VERSION 5.7 ;
  NOWIREEXTENSIONATPIN ON ;
  DIVIDERCHAR "/" ;
  BUSBITCHARS "[]" ;
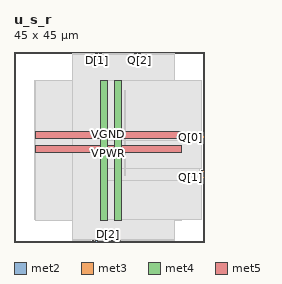
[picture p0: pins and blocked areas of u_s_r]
MACRO u_s_r
  CLASS BLOCK ;
  FOREIGN u_s_r ;
  ORIGIN 0.000 0.000 ;
  SIZE 45.000 BY 45.000 ;
  PIN D[0]
    DIRECTION INPUT ;
    USE SIGNAL ;
    ANTENNAGATEAREA 0.213000 ;
    PORT
      LAYER met2 ;
        RECT 23.090 0.000 23.370 0.280 ;
    END
  END D[0]
  PIN D[1]
    DIRECTION INPUT ;
    USE SIGNAL ;
    ANTENNAGATEAREA 0.213000 ;
    PORT
      LAYER met2 ;
        RECT 19.410 44.720 19.690 45.000 ;
    END
  END D[1]
  PIN D[2]
    DIRECTION INPUT ;
    USE SIGNAL ;
    ANTENNAGATEAREA 0.213000 ;
    PORT
      LAYER met2 ;
        RECT 22.170 0.000 22.450 0.280 ;
    END
  END D[2]
  PIN D[3]
    DIRECTION INPUT ;
    USE SIGNAL ;
    ANTENNAGATEAREA 0.213000 ;
    PORT
      LAYER met2 ;
        RECT 24.930 0.000 25.210 0.280 ;
    END
  END D[3]
  PIN Q[0]
    DIRECTION OUTPUT ;
    USE SIGNAL ;
    ANTENNADIFFAREA 0.702900 ;
    PORT
      LAYER met3 ;
        RECT 44.400 24.520 45.000 25.120 ;
    END
  END Q[0]
  PIN Q[1]
    DIRECTION OUTPUT ;
    USE SIGNAL ;
    ANTENNADIFFAREA 0.702900 ;
    PORT
      LAYER met3 ;
        RECT 44.400 15.000 45.000 15.600 ;
    END
  END Q[1]
  PIN Q[2]
    DIRECTION OUTPUT ;
    USE SIGNAL ;
    ANTENNADIFFAREA 0.702900 ;
    PORT
      LAYER met2 ;
        RECT 29.530 44.720 29.810 45.000 ;
    END
  END Q[2]
  PIN Q[3]
    DIRECTION OUTPUT ;
    USE SIGNAL ;
    ANTENNADIFFAREA 0.702900 ;
    PORT
      LAYER met3 ;
        RECT 44.400 16.360 45.000 16.960 ;
    END
  END Q[3]
  PIN S_in
    DIRECTION INPUT ;
    USE SIGNAL ;
    ANTENNAGATEAREA 0.213000 ;
    PORT
      LAYER met2 ;
        RECT 24.010 0.000 24.290 0.280 ;
    END
  END S_in
  PIN VGND
    DIRECTION INOUT ;
    USE GROUND ;
    PORT
      LAYER met4 ;
        RECT 23.880 5.200 25.480 38.320 ;
    END
    PORT
      LAYER met5 ;
        RECT 5.060 24.590 39.560 26.190 ;
    END
  END VGND
  PIN VPWR
    DIRECTION INOUT ;
    USE POWER ;
    PORT
      LAYER met4 ;
        RECT 20.580 5.200 22.180 38.320 ;
    END
    PORT
      LAYER met5 ;
        RECT 5.060 21.290 39.560 22.890 ;
    END
  END VPWR
  PIN clk
    DIRECTION INPUT ;
    USE SIGNAL ;
    ANTENNAGATEAREA 0.852000 ;
    PORT
      LAYER met2 ;
        RECT 28.610 44.720 28.890 45.000 ;
    END
  END clk
  PIN mode[0]
    DIRECTION INPUT ;
    USE SIGNAL ;
    ANTENNAGATEAREA 0.213000 ;
    PORT
      LAYER met2 ;
        RECT 18.490 0.000 18.770 0.280 ;
    END
  END mode[0]
  PIN mode[1]
    DIRECTION INPUT ;
    USE SIGNAL ;
    ANTENNAGATEAREA 0.213000 ;
    PORT
      LAYER met2 ;
        RECT 19.410 0.000 19.690 0.280 ;
    END
  END mode[1]
  PIN rst
    DIRECTION INPUT ;
    USE SIGNAL ;
    ANTENNAGATEAREA 0.213000 ;
    PORT
      LAYER met2 ;
        RECT 20.330 44.720 20.610 45.000 ;
    END
  END rst
  OBS
      LAYER nwell ;
        RECT 4.870 5.355 39.750 38.165 ;
      LAYER li1 ;
        RECT 5.060 5.355 39.560 38.165 ;
      LAYER met1 ;
        RECT 5.060 5.200 39.560 38.320 ;
      LAYER met2 ;
        RECT 13.900 44.440 19.130 44.720 ;
        RECT 19.970 44.440 20.050 44.720 ;
        RECT 20.890 44.440 28.330 44.720 ;
        RECT 29.170 44.440 29.250 44.720 ;
        RECT 30.090 44.440 38.090 44.720 ;
        RECT 13.900 0.560 38.090 44.440 ;
        RECT 13.900 0.280 18.210 0.560 ;
        RECT 19.050 0.280 19.130 0.560 ;
        RECT 19.970 0.280 21.890 0.560 ;
        RECT 22.730 0.280 22.810 0.560 ;
        RECT 23.650 0.280 23.730 0.560 ;
        RECT 24.570 0.280 24.650 0.560 ;
        RECT 25.490 0.280 38.090 0.560 ;
      LAYER met3 ;
        RECT 20.590 25.520 44.400 38.245 ;
        RECT 20.590 24.120 44.000 25.520 ;
        RECT 20.590 17.360 44.400 24.120 ;
        RECT 20.590 14.600 44.000 17.360 ;
        RECT 20.590 5.275 44.400 14.600 ;
      LAYER met4 ;
        RECT 26.055 15.815 26.385 35.865 ;
  END
END u_s_r
END LIBRARY

